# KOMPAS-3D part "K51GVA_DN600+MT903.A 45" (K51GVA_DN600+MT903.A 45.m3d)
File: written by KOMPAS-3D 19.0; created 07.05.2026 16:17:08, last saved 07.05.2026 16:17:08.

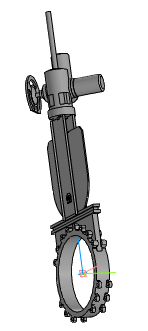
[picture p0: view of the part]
Document properties: Автор: Энергия; Полное имя файла: ..\K51GVA_DN50-DN1000+MT903.A\K51GVA_DN600+MT903.A 45.a3d

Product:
- Part/product: K51GVA_DN600+MT903.A 45
    Масса: 365.253

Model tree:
1. Операция без истории:1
